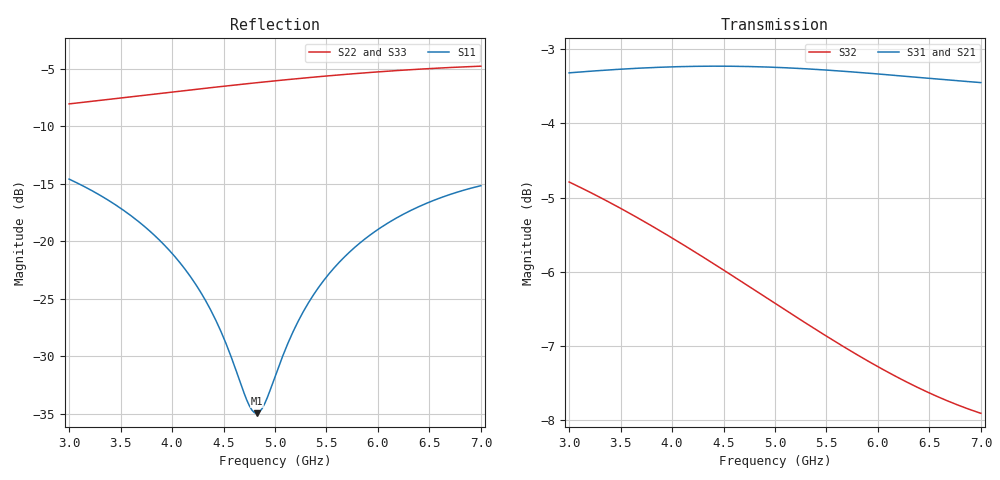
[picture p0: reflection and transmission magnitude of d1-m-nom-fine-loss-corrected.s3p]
! yapnr Order 0 prediction d1-m-nom-fine: predictions/D1/variants/d1-star-m-nom/fine.s3p, loss-corrected
! substrate M-nom; coupon model OSHPARK-4L-FR408HR; correction: ratio (port line)
! |S21|, |S31| (and S12, S13) scaled, phases kept; 50 ohm, e^(+jwt)
# GHz S RI R 50
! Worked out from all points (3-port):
!   161 points, 3 GHz to 7 GHz, reference 50 ohm
!   strongest paths, dB at 3 GHz, 4 GHz, 5 GHz, 6 GHz, 7 GHz:
!     S31: -3.3, -3.2, -3.2, -3.3, -3.4
!     S21: -3.3, -3.2, -3.2, -3.3, -3.4
!     S32: -4.8, -5.5, -6.4, -7.3, -7.9
!   lowest |S11| = -34.9 dB at 4.825 GHz (marker M1), VSWR 1.04, Z = 51.7 - j0.557 ohm
!   |S11| at or under -10 dB: start of sweep to end of sweep
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3  -0.0718 0.1717  0.0988 -0.6754  0.0988 -0.6754
   0.0987 -0.6753  0.1424 0.3684  -0.1531 -0.5554
   0.0987 -0.6753  -0.1531 -0.5554  0.1424 0.3684
3.6  -0.0139 0.1285  -0.1036 -0.6792  -0.1036 -0.6792
     -0.1036 -0.6792  0.2752 0.3224  -0.3184 -0.4462
     -0.1036 -0.6792  -0.3184 -0.4462  0.2752 0.3224
4.075  0.0142 0.0796  -0.261 -0.6379  -0.261 -0.6379
       -0.261 -0.6378  0.3685 0.2557  -0.4074 -0.3301
       -0.261 -0.6378  -0.4074 -0.3301  0.3685 0.2557
4.375  0.0217 0.0454  -0.3539 -0.592  -0.3539 -0.592
       -0.3538 -0.5919  0.4186 0.2012  -0.4431 -0.2504
       -0.3538 -0.5919  -0.4431 -0.2504  0.4186 0.2012
4.825  0.0171 -0.00538  -0.4771 -0.4973  -0.4771 -0.4973
       -0.477 -0.4972  0.4771 0.1041  -0.4681 -0.1304
       -0.477 -0.4972  -0.4681 -0.1304  0.4771 0.1041
5  0.0103 -0.0236  -0.5184 -0.4531  -0.5184 -0.4531
   -0.5183 -0.453  0.4934 0.0623  -0.4695 -0.0852
   -0.5183 -0.453  -0.4695 -0.0852  0.4934 0.0623
5.325  -0.00875 -0.0533  -0.5835 -0.3622  -0.5835 -0.3622
       -0.5834 -0.3621  0.5133 -0.0195  -0.4615 -0.00557
       -0.5834 -0.3621  -0.4615 -0.00557  0.5133 -0.0195
5.725  -0.0415 -0.0796  -0.641 -0.2382  -0.641 -0.2382
       -0.6409 -0.2382  0.5177 -0.1241  -0.4358 0.0827
       -0.6409 -0.2382  -0.4358 0.0827  0.5177 -0.1241
6.3  -0.098 -0.0925  -0.677 -0.0482  -0.677 -0.0482
     -0.6768 -0.0481  0.4843 -0.2719  -0.3773 0.1881
     -0.6768 -0.0481  -0.3773 0.1881  0.4843 -0.2719
7  -0.1614 -0.0658  -0.6476 0.1808  -0.6476 0.1808
   -0.6475 0.1808  0.3866 -0.4269  -0.2855 0.2834
   -0.6475 0.1808  -0.2855 0.2834  0.3866 -0.4269
